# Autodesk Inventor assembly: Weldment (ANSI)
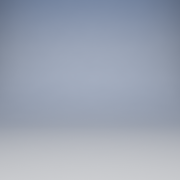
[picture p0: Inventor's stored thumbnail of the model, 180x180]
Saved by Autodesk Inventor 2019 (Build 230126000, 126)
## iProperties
Created: 2018-02
Part Number: Weldment (ANSI)
Material: Všeobecné
Document SubType Name: Weldment
Weld Material: Welded Aluminum-6061
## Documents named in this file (1)
- C:\Users\CSY\Desktop\csy-126\English.Base\Weldment (ANSI).iam
